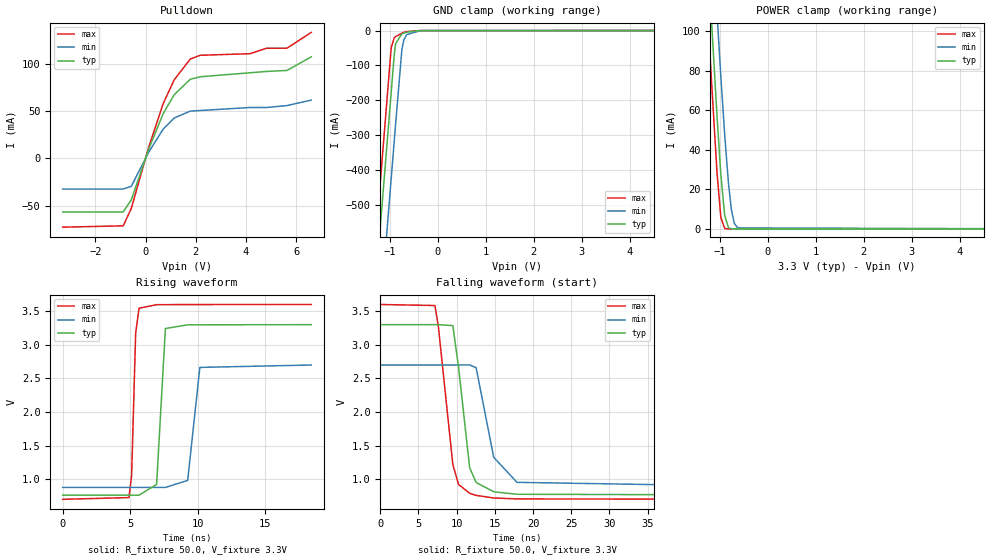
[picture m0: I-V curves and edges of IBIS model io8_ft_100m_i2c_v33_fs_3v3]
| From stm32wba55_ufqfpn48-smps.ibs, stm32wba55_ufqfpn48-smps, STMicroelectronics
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[Model]   io8_ft_100m_i2c_v33_fs_3v3
Model_type I/O_open_drain
Polarity   Non-Inverting
Enable   Active-Low
| CAP_THRESHOLD on pad IOFT is "UDTCAPC" :
| Rising=30.0% of vddiom   Falling=70.0% of vddiom
| C_comp min and max val. don't necessarily correlate with the min and max pvt
| but are the smallest and greatest pad capacitance found.
| var   typ   min   max
C_comp   2.70467pF  2.60096pF  2.73929pF
|C_comp_pulldown   2.70467pF  2.60096pF  2.73929pF
Vinl = 1.35V
Vinh = 1.8V
Vmeas = 1.65V   | Reference voltage for timing measurements
Cref  = 50.0pF   | Timing specification test load capacitance value
Rref  = 1.0MOhm   | Timing specification test load resistance value
Vref  = 1.815V   | Timing specification test load voltage
[Model Spec]
| TIME_THRESHOLD on pin ZII2CV11 is "CMOS" :
| Rising=50.0% of vdd   Falling=50.0% of vdd
Vinl 1.28450V 1.07650V 1.38450V
Vinh 1.79550V 1.49050V 1.94250V
| variable   typ   min   max
[Temperature Range] 25.0 140.0 -40.0
| variable   typ   min   max
[Voltage Range] 3.3V 2.7V 3.6V
| variable   typ   min   max
[POWER Clamp Reference] 3.3V 2.7V 3.6V
| variable   typ   min   max
[GND Clamp Reference] 0V 0V 0V
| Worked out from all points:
|   slope of the pulldown table from 0 to 0.495 V, typ, clamps not added: 14 ohm
|   GND clamp passes 1 mA (typ) near -0.51 V on its own axis
|   POWER clamp passes 1 mA (typ) near -0.83 V on its own axis
|   rising waveform, R_fixture 50.0, V_fixture 3.3V: 20-80 % time 256ps typ, 332ps min, 231ps max; typ from 0.764 V to 3.3 V
|   falling waveform, R_fixture 50.0, V_fixture 3.3V: 20-80 % time 1.43ns typ, 1.93ns min, 1.6ns max; typ from 3.3 V to 0.764 V
[POWER Clamp]
-3.3V     1.123A     1.139A     1.091A
-1.36V    189.2mA    238.8mA    158.1mA
-1.25V    139mA      190.3mA    108.1mA
-1.18V    107.9mA    159.9mA    77.22mA
-1.06V    57.23mA    109.3mA    28.68mA
-980mV    27.6mA     77.28mA    5.935mA
-900mV    6.895mA    47.74mA    242.8uA
-820mV    594.6uA    22.85mA    5.912uA
-760mV    69.41uA    9.714mA    358.6nA
-700mV    7.83uA     2.919mA    21.86nA
-630mV    611.5nA    529.9uA    954.5pA
6.6V      0A         0A         0A
[GND Clamp]
-3.3V     -4.134A    -4.382A    -4.006A
-1.59V    -1.227A    -1.475A    -1.099A
-1.25V    -648.9mA   -896.7mA   -520.9mA
-980mV    -189.9mA   -437.7mA   -61.92mA
-970mV    -172.9mA   -420.7mA   -48.45mA
-910mV    -70.86mA   -318.7mA   -21.03mA
-880mV    -37.23mA   -267.7mA   -17.31mA
-750mV    -9.908mA   -55.25mA   -7.768mA
-710mV    -7.626mA   -27.41mA   -5.608mA
-650mV    -4.885mA   -11.6mA    -3.058mA
-360mV    -31.22uA   -443.6uA   -1.188uA
6.6V      2.31nA     2.655uA    974.6pA
| variable   typ   min   max
[Pullup Reference] 3.3V 2.7V 3.6V
| variable   typ   min   max
[Pulldown Reference] 0V 0V 0V
[Pulldown]
-3.3V     -56.7mA    -32.4mA    -72.73mA
-890mV    -56.7mA    -32.4mA    -71.32mA
-570mV    -43.94mA   -29.54mA   -52.99mA
120mV     9.474mA    6.407mA    11.48mA
700mV     47.33mA    30.97mA    57.88mA
1.14V     67.41mA    42.74mA    83.2mA
1.78V     83.75mA    50.04mA    105.1mA
2.17V     86.37mA    50.65mA    109.1mA
4.16V     90.61mA    53.89mA    110.8mA
4.82V     92.03mA    53.89mA    116.6mA
5.63V     93.04mA    55.89mA    116.6mA
6.6V      107.5mA    61.71mA    133.4mA
[Ramp]
dV/dt_r 1.5215V/251.3114ps 1.09298V/330.66039ps 1.73919V/226.73926ps
dV/dt_f 1.52157V/1.42667ns 1.09312V/1.84546ns 1.73923V/1.57604ns
R_load = 50.0
| Removed startup time: 0s 0s 0s  .
| Removed end time: 18.4ns.
[Rising Waveform]
R_fixture   = 50.0
V_fixture   = 3.3V
V_fixture_min = 2.7V
V_fixture_max = 3.6V
0s        764mV      878.1mV    701.3mV
4.9ns     764mV      878.1mV    727.4mV
5.1ns     764mV      878.1mV    1.055V
5.4ns     764.1mV    878.1mV    3.177V
5.65ns    764mV      878.1mV    3.544V
6.95ns    922.8mV    878.1mV    3.597V
7.6ns     3.243V     878.1mV    3.598V
9.25ns    3.297V     983.2mV    3.599V
10.15ns   3.298V     2.664V     3.599V
18.4ns    3.3V       2.7V       3.6V
| Removed startup time: 0s 0s 0s  .
| Removed end time: 58.35ns.
[Falling Waveform]
R_fixture   = 50.0
V_fixture   = 3.3V
V_fixture_min = 2.7V
V_fixture_max = 3.6V
0s        3.3V       2.7V       3.6V
7.15ns    3.3V       2.7V       3.585V
7.6ns     3.3V       2.7V       3.277V
9.5ns     3.286V     2.7V       1.218V
10.25ns   2.662V     2.7V       922.8mV
11.7ns    1.172V     2.701V     792mV
12.55ns   951.9mV    2.659V     759.8mV
14.85ns   813.8mV    1.326V     721.7mV
17.9ns    776.7mV    954mV      707.4mV
58.35ns   764mV      878.1mV    701.3mV
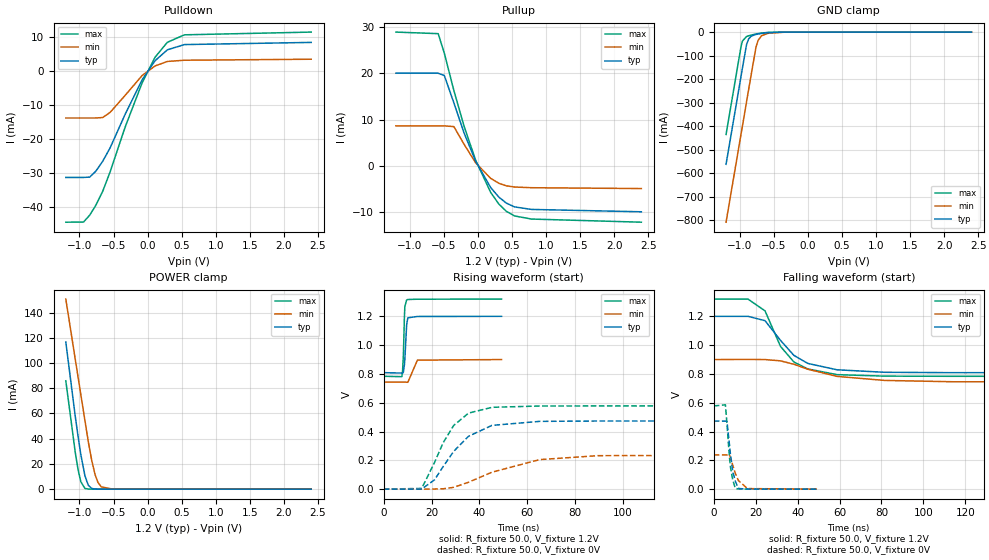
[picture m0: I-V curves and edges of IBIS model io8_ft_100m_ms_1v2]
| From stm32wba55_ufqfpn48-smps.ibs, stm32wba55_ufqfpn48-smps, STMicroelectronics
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[Model]   io8_ft_100m_ms_1v2
Model_type I/O
Polarity   Non-Inverting
Enable   Active-Low
| CAP_THRESHOLD on pad IOFT is "UDTCAPC" :
| Rising=30.0% of vddiom   Falling=70.0% of vddiom
| C_comp min and max val. don't necessarily correlate with the min and max pvt
| but are the smallest and greatest pad capacitance found.
| var   typ   min   max
C_comp   1.75105pF  1.57485pF  1.87845pF
|C_comp_pullup   1.05620pF  962.40500fF  1.08745pF
|C_comp_pulldown   694.85000fF  612.44000fF  790.99500fF
Vinl = 450.0mV
Vinh = 660.0mV
Vmeas = 600.0mV   | Reference voltage for timing measurements
Cref  = 50.0pF   | Timing specification test load capacitance value
Rref  = 1.0MOhm   | Timing specification test load resistance value
Vref  = 660.0mV   | Timing specification test load voltage
[Model Spec]
| TIME_THRESHOLD on pin ZIV11 is "CMOS" :
| Rising=50.0% of vdd   Falling=50.0% of vdd
Vinl 441.50000mV 347.50000mV 471.50000mV
Vinh 755.50000mV 552.50000mV 842.50000mV
| variable   typ   min   max
[Temperature Range] 25.0 140.0 -40.0
| variable   typ   min   max
[Voltage Range] 1.2V 900.0mV 1.32V
| variable   typ   min   max
[POWER Clamp Reference] 1.2V 900.0mV 1.32V
| variable   typ   min   max
[GND Clamp Reference] 0V 0V 0V
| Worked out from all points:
|   slope of the pulldown table from 0 to 0.18 V, typ, clamps not added: 40.6 ohm
|   slope of the pullup table from 0 to 0.18 V, typ, clamps not added: 39.4 ohm
|   GND clamp passes 1 mA (typ) near -0.51 V on its own axis
|   POWER clamp passes 1 mA (typ) near -0.83 V on its own axis
|   rising waveform, R_fixture 50.0, V_fixture 1.2V: 20-80 % time 741ps typ, 1.44ns min, 562ps max; typ from 0.809 V to 1.2 V
|   falling waveform, R_fixture 50.0, V_fixture 1.2V: 20-80 % time 15.3ns typ, 25.3ns min, 12.4ns max; typ from 1.2 V to 0.809 V
|   rising waveform, R_fixture 50.0, V_fixture 0V: 20-80 % time 13.9ns typ, 25ns min, 10.9ns max; typ from 0 V to 0.473 V
|   falling waveform, R_fixture 50.0, V_fixture 0V: 20-80 % time 2.49ns typ, 3.86ns min, 2.12ns max; typ from 0.473 V to 0 V
[POWER Clamp]
-1.2V     116.7mA    150.7mA    85.92mA
-1.06V    57.23mA    102.6mA    28.68mA
-1.02V    41.75mA    88.91mA    15.5mA
-980mV    27.6mA     75.18mA    5.935mA
-920mV    10.75mA    54.6mA     597.6uA
-870mV    3.065mA    37.68mA    60.82uA
-820mV    594.6uA    22.85mA    5.912uA
-770mV    99.71uA    11.47mA    572nA
-730mV    23.34uA    5.552mA    88.29nA
-680mV    3.779uA    1.833mA    8.565nA
-510mV    7.889nA    23.13uA    53.67pA
2.4V      0A         0A         0A
[GND Clamp]
-1.2V     -561.6mA   -807.5mA   -434.8mA
-980mV    -187.6mA   -433.5mA   -60.76mA
-960mV    -153.6mA   -399.5mA   -38.21mA
-900mV    -54.17mA   -297.5mA   -18.87mA
-870mV    -29.55mA   -246.5mA   -15.73mA
-830mV    -17.05mA   -178.5mA   -12.57mA
-760mV    -9.921mA   -62.77mA   -8.045mA
-730mV    -8.191mA   -35.56mA   -6.403mA
-680mV    -5.826mA   -15.57mA   -4.089mA
-580mV    -2.43mA    -5.043mA   -1.157mA
-330mV    -11.72uA   -245.5uA   -300.5nA
2.4V      872pA      1.056uA    338.3pA
| variable   typ   min   max
[Pullup Reference] 1.2V 900.0mV 1.32V
| variable   typ   min   max
[Pulldown Reference] 0V 0V 0V
[Pullup]
-1.2V     20.06mA    8.629mA    28.99mA
-580mV    20.06mA    8.629mA    28.65mA
-490mV    19.55mA    8.629mA    24.4mA
-350mV    13.61mA    8.456mA    16.3mA
-200mV    7.069mA    4.622mA    8.528mA
-30mV     926.7uA    571.2uA    1.132mA
190mV     -4.777mA   -2.782mA   -5.837mA
310mV     -6.857mA   -3.851mA   -8.366mA
420mV     -8.158mA   -4.403mA   -9.943mA
540mV     -8.979mA   -4.661mA   -10.94mA
790mV     -9.528mA   -4.812mA   -11.62mA
2.4V      -10.04mA   -4.994mA   -12.3mA
[Pulldown]
-1.2V     -31.2mA    -13.81mA   -44.3mA
-940mV    -31.2mA    -13.81mA   -44.26mA
-850mV    -31.11mA   -13.81mA   -42.26mA
-760mV    -29.39mA   -13.81mA   -39.38mA
-660mV    -26.52mA   -13.68mA   -35.32mA
-550mV    -22.55mA   -12.17mA   -29.6mA
-330mV    -12.74mA   -7.204mA   -16.5mA
-80mV     -2.622mA   -1.37mA    -3.49mA
110mV     2.963mA    1.428mA    3.999mA
290mV     6.144mA    2.737mA    8.347mA
540mV     7.674mA    3.096mA    10.53mA
2.4V      8.312mA    3.389mA    11.33mA
[Ramp]
dV/dt_r 283.79647mV/13.84572ns 142.77625mV/24.44281ns 346.6203mV/10.79298ns
dV/dt_f 234.6598mV/15.11947ns 93.7648mV/24.5094ns 321.77307mV/12.30416ns
R_load = 50.0
| Removed startup time: 0s 0s 0s  .
| Removed end time: 49.25ns.
[Rising Waveform]
R_fixture   = 50.0
V_fixture   = 1.2V
V_fixture_min = 900.0mV
V_fixture_max = 1.32V
0s        808.9mV    743.7mV    783.7mV
7.6ns     805.9mV    743.8mV    780.9mV
7.9ns     804.3mV    743.8mV    819.9mV
8.25ns    812.9mV    743.7mV    930.4mV
8.65ns    859.9mV    743.6mV    1.183V
8.85ns    899.9mV    743.5mV    1.268V
9.6ns     1.14V      742.6mV    1.314V
10.1ns    1.19V      741.9mV    1.317V
14.1ns    1.199V     895.7mV    1.319V
49.25ns   1.2V       899.8mV    1.32V
| Removed startup time: 0s 0s 0s  .
| Removed end time: 399.2ns.
[Falling Waveform]
R_fixture   = 50.0
V_fixture   = 1.2V
V_fixture_min = 900.0mV
V_fixture_max = 1.32V
0s        1.2V       900mV      1.32V
16.3ns    1.2V       900.9mV    1.32V
24.45ns   1.17V      900mV      1.238V
31.85ns   1.033V     890.9mV    990.9mV
38.2ns    929.2mV    867.4mV    883.4mV
44.85ns   873.1mV    832.9mV    834.9mV
58.85ns   828.8mV    782.9mV    795.1mV
81.5ns    811.6mV    755.1mV    784.9mV
114.1ns   808.9mV    745.8mV    783.7mV
399.2ns   808.9mV    743.7mV    783.7mV
| Removed startup time: 0s 0s 0s  .
| Removed end time: 399.2ns.
[Rising Waveform]
R_fixture   = 50.0
V_fixture   = 0V
V_fixture_min = 0V
V_fixture_max = 0V
0s        4.648nV    985.6nV    3.924nV
15.9ns    122.5uV    -477.7uV   4.731mV
21.25ns   64.24mV    606.1uV    185.1mV
24.9ns    157.4mV    2.156mV    323.2mV
29.25ns   262mV      12.26mV    441.6mV
35.45ns   366.7mV    47.5mV     527.8mV
45.25ns   442.5mV    117.4mV    568mV
65.2ns    470.5mV    204.9mV    577.1mV
89.65ns   472.8mV    232.4mV    577.6mV
399.2ns   473mV      238mV      577.7mV
| Removed startup time: 0s 0s 0s  .
| Removed end time: 49.25ns.
[Falling Waveform]
R_fixture   = 50.0
V_fixture   = 0V
V_fixture_min = 0V
V_fixture_max = 0V
0s        473mV      238mV      577.7mV
5.55ns    472.6mV    238mV      585.7mV
6.3ns     470.5mV    237.8mV    452.7mV
7.3ns     333.9mV    242.1mV    253.4mV
7.95ns    243.4mV    221.2mV    152.7mV
9.05ns    122.1mV    166.3mV    64.2mV
10.3ns    53.76mV    109.2mV    4.906mV
11.8ns    4.622mV    58.82mV    1.746mV
16.1ns    634.5uV    4.06mV     507.4uV
49.25ns   46.84uV    100.2uV    26.87uV
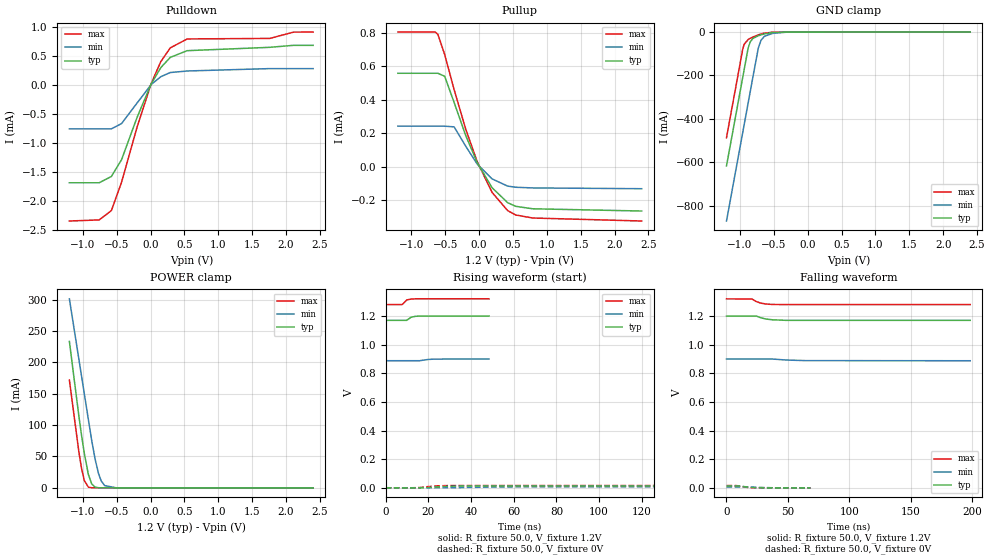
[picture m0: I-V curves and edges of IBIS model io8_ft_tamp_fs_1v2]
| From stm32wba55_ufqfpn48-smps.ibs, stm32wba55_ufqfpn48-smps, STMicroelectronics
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[Model]   io8_ft_tamp_fs_1v2
Model_type I/O
Polarity   Non-Inverting
Enable   Active-Low
| CAP_THRESHOLD on pad IOFT is "UDTCAPC" :
| Rising=30.0% of vddiom   Falling=70.0% of vddiom
| C_comp min and max val. don't necessarily correlate with the min and max pvt
| but are the smallest and greatest pad capacitance found.
| var   typ   min   max
C_comp   4.69898pF  4.28274pF  4.82427pF
|C_comp_pullup   2.96083pF  2.69783pF  2.96537pF
|C_comp_pulldown   1.73815pF  1.58490pF  1.85890pF
Vinl = 450.0mV
Vinh = 660.0mV
Vmeas = 600.0mV   | Reference voltage for timing measurements
Cref  = 50.0pF   | Timing specification test load capacitance value
Rref  = 1.0MOhm   | Timing specification test load resistance value
Vref  = 660.0mV   | Timing specification test load voltage
[Model Spec]
| TIME_THRESHOLD on pin ZIV33SW is "CMOS" :
| Rising=50.0% of VDDV33SW   Falling=50.0% of VDDV33SW
Vinl 436.50000mV 342.50000mV 466.50000mV
Vinh 753.50000mV 549.50000mV 839.50000mV
| variable   typ   min   max
[Temperature Range] 25.0 140.0 -40.0
| variable   typ   min   max
[Voltage Range] 1.2V 900.0mV 1.32V
| variable   typ   min   max
[POWER Clamp Reference] 1.2V 900.0mV 1.32V
| variable   typ   min   max
[GND Clamp Reference] 0V 0V 0V
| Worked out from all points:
|   slope of the pulldown table from 0 to 0.18 V, typ, clamps not added: 517 ohm
|   slope of the pullup table from 0 to 0.18 V, typ, clamps not added: 1.49 kohm
|   GND clamp passes 1 mA (typ) near -0.47 V on its own axis
|   POWER clamp passes 1 mA (typ) near -0.81 V on its own axis
[POWER Clamp]
-1.2V     233.4mA    301.3mA    171.8mA
-1.06V    114.5mA    205.3mA    57.35mA
-1.02V    83.5mA     177.8mA    30.99mA
-980mV    55.21mA    150.4mA    11.87mA
-920mV    21.5mA     109.2mA    1.195mA
-870mV    6.13mA     75.36mA    121.6uA
-820mV    1.189mA    45.7mA     11.82uA
-770mV    199.4uA    22.94mA    1.144uA
-730mV    46.68uA    11.1mA     176.6nA
-680mV    7.557uA    3.666mA    17.16nA
-510mV    15.46nA    46.13uA    134.2pA
2.4V      0A         0A         0A
[GND Clamp]
-1.2V     -616.6mA   -870.4mA   -486.7mA
-960mV    -208.6mA   -462.4mA   -78.75mA
-940mV    -174.6mA   -428.4mA   -56.97mA
-880mV    -73.49mA   -326.4mA   -34.53mA
-850mV    -45.28mA   -275.4mA   -29.09mA
-810mV    -29.66mA   -207.4mA   -23mA
-730mV    -17.09mA   -73.72mA   -13.06mA
-690mV    -13mA      -37.99mA   -9.157mA
-640mV    -8.81mA    -19.57mA   -5.341mA
-520mV    -2.385mA   -6.292mA   -748.7uA
-300mV    -8.501uA   -273.8uA   -150.7nA
2.4V      1.845nA    2.377uA    739.2pA
| variable   typ   min   max
[Pullup Reference] 1.2V 900.0mV 1.32V
| variable   typ   min   max
[Pulldown Reference] 0V 0V 0V
[Pullup]
-1.2V     556.9uA    241.1uA    803uA
-650mV    556.9uA    241.1uA    803uA
-610mV    556.9uA    241.1uA    789uA
-510mV    539.1uA    241.1uA    669.2uA
-370mV    382.5uA    236.9uA    459uA
-200mV    186.4uA    122.2uA    224.9uA
-30mV     24.45uA    15.08uA    29.88uA
190mV     -126.1uA   -73.56uA   -154.1uA
420mV     -215.5uA   -116.6uA   -262.7uA
540mV     -237.4uA   -123.5uA   -289.1uA
790mV     -252uA     -127.5uA   -307.1uA
2.4V      -265.4uA   -132.2uA   -325uA
[Pulldown]
-1.2V     -1.691mA   -757.3uA   -2.353mA
-760mV    -1.691mA   -757.3uA   -2.334mA
-580mV    -1.582mA   -757.3uA   -2.173mA
-430mV    -1.293mA   -666.6uA   -1.684mA
-200mV    -558.4uA   -310.3uA   -726.5uA
10mV      24.06uA    11.99uA    32.4uA
150mV     302.2uA    144.8uA    405.5uA
290mV     480.2uA    217.4uA    644uA
540mV     595.8uA    244.2uA    798.9uA
1.76V     653.9uA    285.4uA    807.9uA
2.11V     688.3uA    285.4uA    916.9uA
2.4V      688.3uA    285.4uA    918.5uA
[Ramp]
dV/dt_r 7.74329mV/8.42289ns 3.84636mV/15.2167ns 9.49193mV/6.51789ns
dV/dt_f 18.01407mV/8.79181ns 7.34446mV/14.8475ns 24.13958mV/7.28023ns
R_load = 50.0
| Removed startup time: 0s 0s 0s  .
| Removed end time: 48.4ns.
[Rising Waveform]
R_fixture   = 50.0
V_fixture   = 1.2V
V_fixture_min = 900.0mV
V_fixture_max = 1.32V
0s        1.17V      887.8mV    1.28V
7.55ns    1.17V      887.8mV    1.28V
8ns       1.17V      887.8mV    1.284V
9.8ns     1.17V      887.8mV    1.312V
11.85ns   1.191V     887.8mV    1.319V
13.85ns   1.198V     887.8mV    1.32V
15.8ns    1.2V       887.7mV    1.32V
19.85ns   1.2V       896.5mV    1.32V
22.75ns   1.2V       899.1mV    1.32V
48.4ns    1.2V       900mV      1.32V
| Removed startup time: 0s 0s 0s  .
| Removed end time: 198.4ns.
[Falling Waveform]
R_fixture   = 50.0
V_fixture   = 1.2V
V_fixture_min = 900.0mV
V_fixture_max = 1.32V
0s        1.2V       900mV      1.32V
20.85ns   1.2V       900.1mV    1.319V
23ns      1.2V       900mV      1.307V
24.3ns    1.2V       900mV      1.301V
27.95ns   1.188V     900mV      1.29V
32.3ns    1.179V     900mV      1.284V
37.15ns   1.174V     899.9mV    1.281V
48.6ns    1.17V      892.8mV    1.28V
64.8ns    1.17V      888.6mV    1.28V
198.4ns   1.17V      887.8mV    1.28V
| Removed startup time: 0s 0s 0s  .
| Removed end time: 198.35ns.
[Rising Waveform]
R_fixture   = 50.0
V_fixture   = 0V
V_fixture_min = 0V
V_fixture_max = 0V
0s        19.98nV    4.257uV    19.22nV
12.15ns   -639.9uV   4.557uV    -429.3uV
16.2ns    -119.2uV   -101.3uV   2.073mV
18.75ns   359.9uV    -308.9uV   6.549mV
24.45ns   6.694mV    -122.4uV   13.51mV
28.7ns    10.1mV     131.4uV    15.12mV
32.6ns    11.61mV    541.7uV    15.67mV
49.45ns   12.89mV    5.014mV    15.83mV
62.85ns   12.91mV    6.154mV    15.82mV
198.3ns   12.91mV    6.415mV    15.82mV
| Removed startup time: 0s 0s 0s  .
| Removed end time: 68.4ns.
[Falling Waveform]
R_fixture   = 50.0
V_fixture   = 0V
V_fixture_min = 0V
V_fixture_max = 0V
0s        12.91mV    6.42mV     15.82mV
8.15ns    12.91mV    6.42mV     15.82mV
11.2ns    12.53mV    6.42mV     11.02mV
15.85ns   7.099mV    6.418mV    4.412mV
18.25ns   4.734mV    6.436mV    2.076mV
20.95ns   2.513mV    5.509mV    830.9uV
23.75ns   1.011mV    4.369mV    271.4uV
27.95ns   286.2uV    2.847mV    112.8uV
37.7ns    42.32uV    586uV      11.67uV
68.4ns    -262.7nV   14.62uV    24.39nV
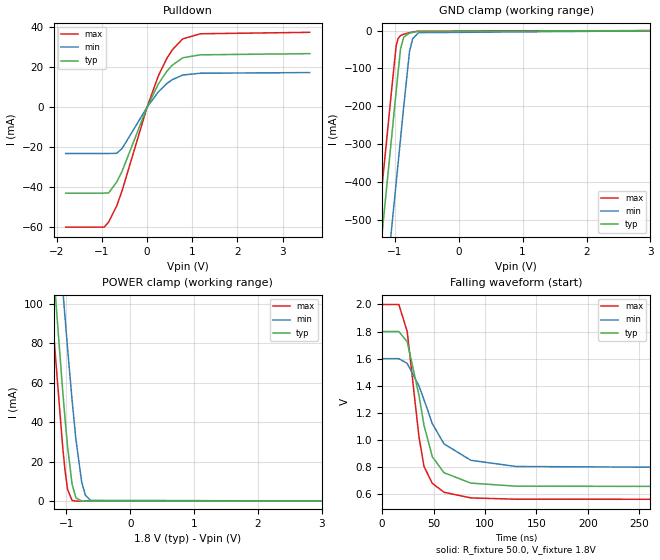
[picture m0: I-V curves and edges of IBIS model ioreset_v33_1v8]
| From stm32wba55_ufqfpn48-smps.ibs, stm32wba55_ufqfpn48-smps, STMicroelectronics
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[Model]   ioreset_v33_1v8
Model_type I/O_open_drain
Polarity   Inverting
Enable   Active-Low
| CAP_THRESHOLD on pad IOFT is "UDTCAPC" :
| Rising=30.0% of vddiom   Falling=70.0% of vddiom
| C_comp min and max val. don't necessarily correlate with the min and max pvt
| but are the smallest and greatest pad capacitance found.
| var   typ   min   max
C_comp   1.34960pF  1.28665pF  1.44035pF
|C_comp_pulldown   1.34960pF  1.28665pF  1.44035pF
Vinl = 800.0mV
Vinh = 1.0V
Vmeas = 900.0mV   | Reference voltage for timing measurements
Cref  = 50.0pF   | Timing specification test load capacitance value
Rref  = 1.0MOhm   | Timing specification test load resistance value
Vref  = 990.0mV   | Timing specification test load voltage
[Model Spec]
| TIME_THRESHOLD on pin ZIV33M is "CMOS" :
| Rising=50.0% of vddiom   Falling=50.0% of vddiom
Vinl 700.50000mV 639.50000mV 768.50000mV
Vinh 1.08250V 937.50000mV 1.21250V
| variable   typ   min   max
[Temperature Range] 25.0 140.0 -40.0
| variable   typ   min   max
[Voltage Range] 1.8V 1.6V 2.0V
| variable   typ   min   max
[POWER Clamp Reference] 1.8V 1.6V 2.0V
| variable   typ   min   max
[GND Clamp Reference] 0V 0V 0V
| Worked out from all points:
|   slope of the pulldown table from 0 to 0.27 V, typ, clamps not added: 21.9 ohm
|   GND clamp passes 1 mA (typ) near -0.54 V on its own axis
|   POWER clamp passes 1 mA (typ) near -0.83 V on its own axis
|   falling waveform, R_fixture 50.0, V_fixture 1.8V: 20-80 % time 18.5ns typ, 28.3ns min, 13.6ns max; typ from 1.8 V to 0.655 V
[POWER Clamp]
-1.8V     396.4mA    438.1mA    365.5mA
-1.26V    143.5mA    194.6mA    112.6mA
-1.19V    112.3mA    164.2mA    81.56mA
-1.06V    57.23mA    109.3mA    28.68mA
-1.02V    41.75mA    93.06mA    15.5mA
-980mV    27.6mA     77.28mA    5.935mA
-910mV    8.693mA    51.24mA    382.3uA
-850mV    1.642mA    31.41mA    23.97uA
-760mV    69.41uA    9.714mA    358.5nA
-700mV    7.83uA     2.919mA    21.77nA
-620mV    424.4nA    410.6uA    553.9pA
3.6V      0A         0A         0A
[GND Clamp]
-1.8V     -1.557A    -1.798A    -1.432A
-1.37V    -825.8mA   -1.067A    -700.6mA
-1.24V    -604.8mA   -845.7mA   -479.6mA
-1.05V    -281.8mA   -522.7mA   -156.6mA
-980mV    -162.8mA   -403.7mA   -41.36mA
-950mV    -111.8mA   -352.7mA   -21.48mA
-910mV    -47.69mA   -284.7mA   -13.34mA
-860mV    -17.27mA   -199.7mA   -9.699mA
-770mV    -6.959mA   -54.68mA   -5.601mA
-720mV    -5.009mA   -21.68mA   -3.812mA
-630mV    -2.532mA   -5.774mA   -1.494mA
3.6V      390pA      176.4nA    255.7pA
| variable   typ   min   max
[Pullup Reference] 1.8V 1.6V 2.0V
| variable   typ   min   max
[Pulldown Reference] 0V 0V 0V
[Pulldown]
-1.8V     -42.95mA   -23.13mA   -59.97mA
-950mV    -42.95mA   -23.13mA   -59.97mA
-850mV    -42.85mA   -23.13mA   -57.42mA
-670mV    -37.39mA   -23.01mA   -49.26mA
-550mV    -31.88mA   -20.59mA   -41.56mA
0V        0A         0A         0A
250mV     11.65mA    7.685mA    15.7mA
440mV     18.05mA    11.87mA    24.51mA
560mV     21.06mA    13.81mA    28.75mA
790mV     24.73mA    16.11mA    34.2mA
1.18V     26.22mA    17.01mA    36.75mA
3.6V      26.81mA    17.34mA    37.47mA
[Ramp]
dV/dt_r 685.00473mV/314.23216ps 484.13117mV/505.51826ps 865.71045mV/228.5844ps
dV/dt_f 687.01105mV/18.33799ns 484.1549mV/28.24688ns 863.47319mV/13.18476ns
R_load = 50.0
| Removed startup time: 0s 0s 0s  .
| Removed end time: 399.25ns.
[Falling Waveform]
R_fixture   = 50.0
V_fixture   = 1.8V
V_fixture_min = 1.6V
V_fixture_max = 2.0V
0s        1.8V       1.6V       2V
16.3ns    1.8V       1.6V       2V
24.45ns   1.725V     1.565V     1.8V
35.9ns    1.328V     1.398V     1.021V
40.75ns   1.108V     1.297V     804.1mV
48.9ns    874.5mV    1.119V     678.5mV
60.2ns    757.7mV    970.6mV    613mV
86.3ns    680.6mV    849.1mV    571.4mV
130.4ns   657.9mV    803.4mV    561.7mV
399.3ns   655mV      793.1mV    560.9mV
